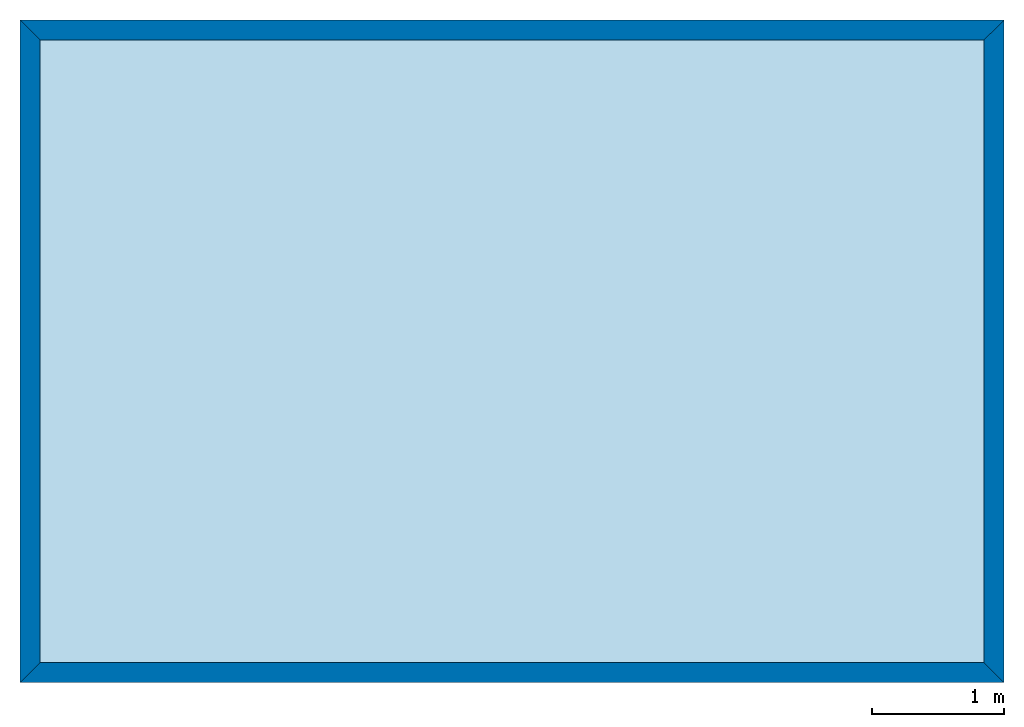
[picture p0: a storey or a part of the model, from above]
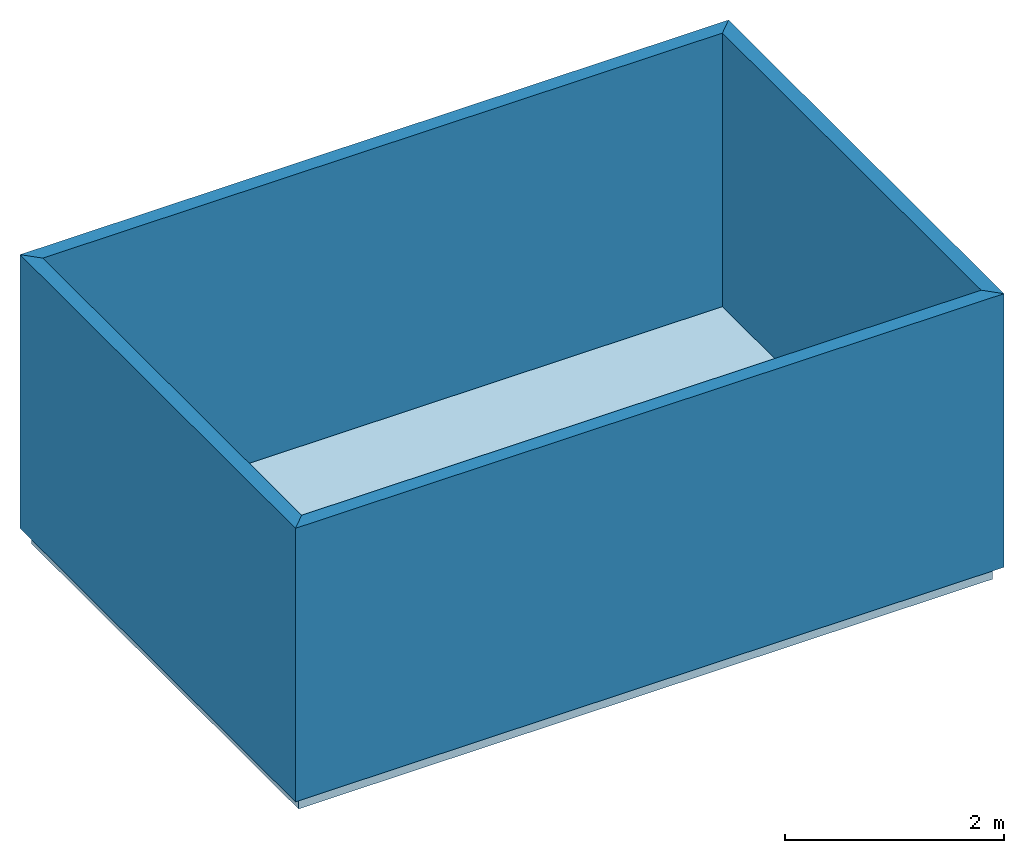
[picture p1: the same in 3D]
Properties of the parts of a building model (IFC4X3_ADD2)

# File
Description: ViewDefinition [notYetAssigned], Comment [manual creation of example file]
File name: construction-scheduling-task.ifc
Time: 2010-09-23T23:27:15
Author: redacted
Organization: redacted
Written by: redacted
Made in: redacted
Authorization: reference file created for the IFC4 specification
Comment: NOTE a valid model view name has to be asserted, replacing 'notYetAssigned'
Comment: NOTE standard header information according to ISO 10303-21
Comment: Project context
Comment: required for every IFC data file
Comment: Project units
Comment: this project is based on imperial units (inch)
Comment: Project
Comment: declaring units, representation context and owner history for this data set
Comment: Spatial structure of site, building, and single storey
Comment: the site has a footprint and body geometric representation
Comment: the building has a footprint geometric representation
Comment: the building storey has a footprint geometric representation
Comment: Slab having rectangular shape and concrete material layer
Comment: Walls for exterior, positioned along edges of rectangular slab
Comment: Standard case walls #1 with axis and body geometry and material layer set defined
Comment: Standard case walls #2 with axis and body geometry and material layer set defined
Comment: Standard case walls #3 with axis and body geometry and material layer set defined
Comment: Standard case walls #4 with axis and body geometry and material layer set defined
Comment: Root task
Comment: Scheduled start is specified which constrains the start of all descendent tasks
Comment: Tasks for slabs, where each nested task is assigned to a specific slab
Comment: Scheduled start and finish are not specified, such that early start and finish take effect --
Comment: Tasks for walls where each nested task is assigned to a specific wall
Comment: Sequences of tasks where each wall must be constructed after supporting slab
Comment: Sequences of tasks indicating order of wall construction; otherwise could be omitted if
Comment: scheduled in parallel
Comment: Work plan includes a set of related calendars and schedules,
Comment: each having assigned tasks and resources
Comment: Work calendar indicates work hours of 08:00-16:00 Monday thru Friday; the calendar is applied
Comment: to the root task and indirectly to all descendent tasks unless overridden
Comment: Work schedule specifies a view of tasks using planned times

# IfcBuildingStorey, Ground Level
In: Building #1
Elevation: 0 in

# IfcSlab, Slab #1
In: Ground Level
PredefinedType: BASESLAB; Material: Concrete (Nominal) 6 in

# IfcTask (8)
IsMilestone: no
Name
Ground Level
Slab (Standard) | Identification: IfcSlabStandardCase
Slab #1
Wall (Standard) | Identification: IfcWallStandardCase
Wall #1
Wall #2
Wall #3
Wall #4

# IfcWall (4)
In: Ground Level
Material: Block (Nominal) 6 in
Name
Wall #1
Wall #2
Wall #3
Wall #4

# IfcWorkCalendar
PredefinedType: FIRSTSHIFT

# IfcWorkPlan, Work Plan #1
CreationDate: 2010-09-23T16:26:16; StartTime: 2010-09-23T00:00:00

# IfcWorkSchedule
CreationDate: 2010-09-23T16:26:42; StartTime: 2010-09-23T00:00:00; PredefinedType: PLANNED
